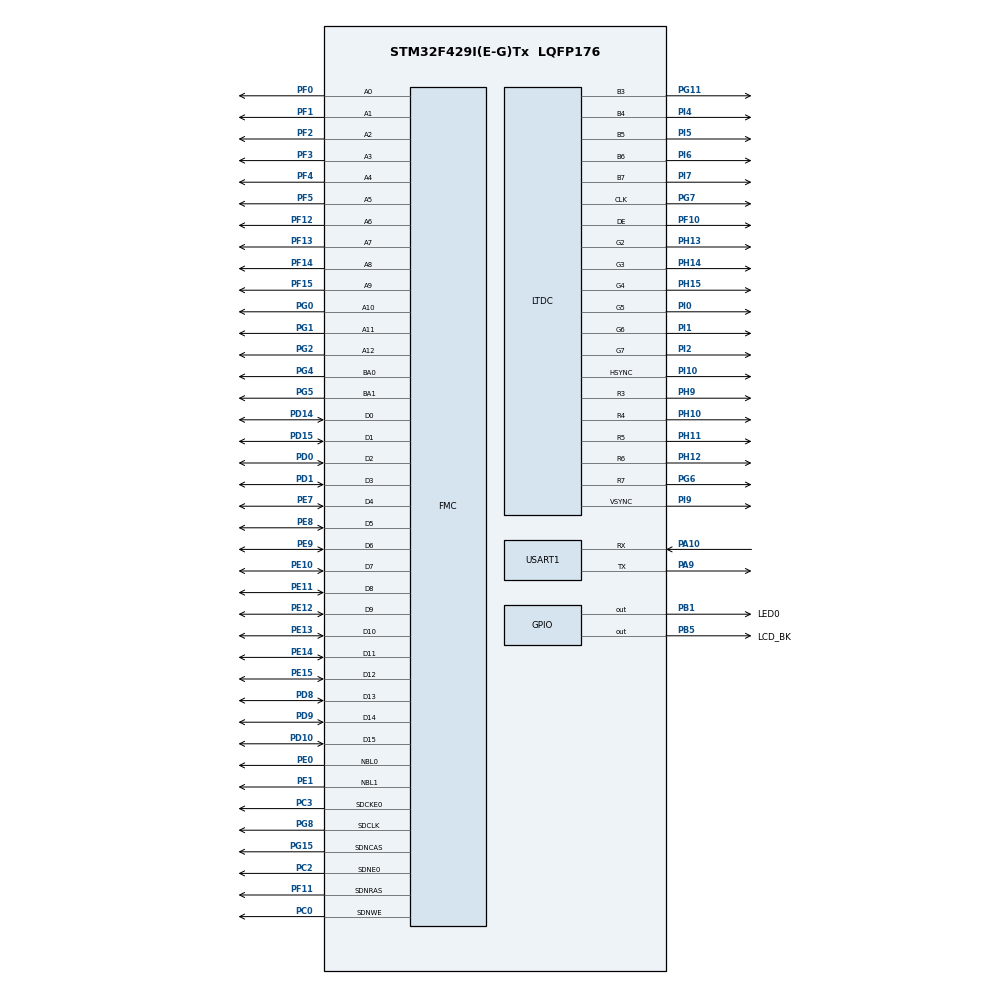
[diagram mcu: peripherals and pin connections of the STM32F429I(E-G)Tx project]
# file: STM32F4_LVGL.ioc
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DMA2D.ColorMode=DMA2D_OUTPUT_RGB565
FMC.CASLatency1=FMC_SDRAM_CAS_LATENCY_3
FMC.ColumnBitsNumber1=FMC_SDRAM_COLUMN_BITS_NUM_9
FMC.ExitSelfRefreshDelay1=7
FMC.LoadToActiveDelay1=2
FMC.RCDDelay1=2
FMC.RPDelay1=2
FMC.RPDelay2=2
FMC.ReadBurst1=FMC_SDRAM_RBURST_ENABLE
FMC.ReadBurst2=FMC_SDRAM_RBURST_ENABLE
FMC.ReadPipeDelay1=FMC_SDRAM_RPIPE_DELAY_0
FMC.RowCycleDelay1=7
FMC.RowCycleDelay2=7
FMC.SDClockPeriod1=FMC_SDRAM_CLOCK_PERIOD_2
FMC.SDClockPeriod2=FMC_SDRAM_CLOCK_PERIOD_2
FMC.SelfRefreshTime1=5
FMC.WriteRecoveryTime1=3
FREERTOS.Tasks01=defaultTask,0,128,StartDefaultTask,Default,NULL,Dynamic,NULL,NULL;myTask02,-3,128,StartTask02,Default,NULL,Dynamic,NULL,NULL;myTask03,-3,128,StartTask03,Default,NULL,Dynamic,NULL,NULL
LTDC.ActiveH=PIXELS_H
LTDC.ActiveW=PIXELS_W
LTDC.Alpha_L0=255
LTDC.FBStartAdress_L0=LTDC_BUFF_ADDR
LTDC.HBP=140
LTDC.HFP=160
LTDC.HSync=20
LTDC.Layers=0
LTDC.PixelFormat_L0=LTDC_PIXEL_FORMAT_RGB565
LTDC.VBP=20
LTDC.VFP=12
LTDC.VSync=3
LTDC.WindowX1_L0=PIXELS_W
LTDC.WindowY1_L0=PIXELS_H
Mcu.Family=STM32F4
Mcu.Name=STM32F429I(E-G)Tx
Mcu.Package=LQFP176
Mcu.UserConstants=LTDC_BUFF_ADDR,0xC0000000;PIXELS_W,1024;PIXELS_H,600;PIXELS_DIR,0
NVIC.PriorityGroup=NVIC_PRIORITYGROUP_4
NVIC.TIM1_UP_TIM10_IRQn=true\:15\:0\:false\:false\:true\:false\:false\:true\:true
NVIC.TimeBase=TIM1_UP_TIM10_IRQn
NVIC.TimeBaseIP=TIM1
NVIC.USART1_IRQn=true\:5\:0\:false\:false\:true\:true\:true\:true\:true
PA10.Mode=Asynchronous
PA10.Signal=USART1_RX
PA9.Mode=Asynchronous
PA9.Signal=USART1_TX
PB1.GPIO_Label=LED0
PB1.Signal=GPIO_Output
PB5.GPIO_Label=LCD_BK
PB5.Signal=GPIO_Output
PC0.Signal=FMC_SDNWE
PC14/OSC32_IN.Mode=LSE-External-Oscillator
PC14/OSC32_IN.Signal=RCC_OSC32_IN
PC15/OSC32_OUT.Mode=LSE-External-Oscillator
PC15/OSC32_OUT.Signal=RCC_OSC32_OUT
PC2.Mode=SdramChipSelect1_1
PC2.Signal=FMC_SDNE0
PC3.Mode=SdramChipSelect1_1
PC3.Signal=FMC_SDCKE0
PD0.Signal=FMC_D2_DA2
PD1.Signal=FMC_D3_DA3
PD10.Signal=FMC_D15_DA15
PD14.Signal=FMC_D0_DA0
PD15.Signal=FMC_D1_DA1
PD8.Signal=FMC_D13_DA13
PD9.Signal=FMC_D14_DA14
PE0.Signal=FMC_NBL0
PE1.Signal=FMC_NBL1
PE10.Signal=FMC_D7_DA7
PE11.Signal=FMC_D8_DA8
PE12.Signal=FMC_D9_DA9
PE13.Signal=FMC_D10_DA10
PE14.Signal=FMC_D11_DA11
PE15.Signal=FMC_D12_DA12
PE7.Signal=FMC_D4_DA4
PE8.Signal=FMC_D5_DA5
PE9.Signal=FMC_D6_DA6
PF0.Signal=FMC_A0
PF1.Signal=FMC_A1
PF10.Mode=RGB565
PF10.Signal=LTDC_DE
PF11.Signal=FMC_SDNRAS
PF12.Signal=FMC_A6
PF13.Signal=FMC_A7
PF14.Signal=FMC_A8
PF15.Signal=FMC_A9
PF2.Signal=FMC_A2
PF3.Signal=FMC_A3
PF4.Signal=FMC_A4
PF5.Signal=FMC_A5
PG0.Signal=FMC_A10
PG1.Signal=FMC_A11
PG11.Mode=RGB565
PG11.Signal=LTDC_B3
PG15.Signal=FMC_SDNCAS
PG2.Signal=FMC_A12
PG4.Signal=FMC_A14_BA0
PG5.Signal=FMC_A15_BA1
PG6.Mode=RGB565
PG6.Signal=LTDC_R7
PG7.Mode=RGB565
PG7.Signal=LTDC_CLK
PG8.Signal=FMC_SDCLK
PH0/OSC_IN.Mode=HSE-External-Oscillator
PH0/OSC_IN.Signal=RCC_OSC_IN
PH1/OSC_OUT.Mode=HSE-External-Oscillator
PH1/OSC_OUT.Signal=RCC_OSC_OUT
PH10.Mode=RGB565
PH10.Signal=LTDC_R4
PH11.Mode=RGB565
PH11.Signal=LTDC_R5
PH12.Mode=RGB565
PH12.Signal=LTDC_R6
PH13.Mode=RGB565
PH13.Signal=LTDC_G2
PH14.Mode=RGB565
PH14.Signal=LTDC_G3
PH15.Mode=RGB565
PH15.Signal=LTDC_G4
PH9.Mode=RGB565
PH9.Signal=LTDC_R3
PI0.Mode=RGB565
PI0.Signal=LTDC_G5
PI1.Mode=RGB565
PI1.Signal=LTDC_G6
PI10.Mode=RGB565
PI10.Signal=LTDC_HSYNC
PI2.Mode=RGB565
PI2.Signal=LTDC_G7
PI4.Mode=RGB565
PI4.Signal=LTDC_B4
PI5.Mode=RGB565
PI5.Signal=LTDC_B5
PI6.Mode=RGB565
PI6.Signal=LTDC_B6
PI7.Mode=RGB565
PI7.Signal=LTDC_B7
PI9.Mode=RGB565
PI9.Signal=LTDC_VSYNC
ProjectManager.HeapSize=0x200
ProjectManager.StackSize=0x400
ProjectManager.TargetToolchain=MDK-ARM V5.32
RCC.48MHZClocksFreq_Value=90000000
RCC.AHBFreq_Value=180000000
RCC.APB1CLKDivider=RCC_HCLK_DIV4
RCC.APB1Freq_Value=45000000
RCC.APB1TimFreq_Value=90000000
RCC.APB2CLKDivider=RCC_HCLK_DIV2
RCC.APB2Freq_Value=90000000
RCC.APB2TimFreq_Value=180000000
RCC.CortexFreq_Value=180000000
RCC.HCLKFreq_Value=180000000
RCC.HSE_VALUE=25000000
RCC.HSI_VALUE=16000000
RCC.PLLN=216
RCC.PLLSAIR=2
RCC.PLLSourceVirtual=RCC_PLLSOURCE_HSE
RCC.SYSCLKFreq_VALUE=180000000
RCC.SYSCLKSource=RCC_SYSCLKSOURCE_PLLCLK
RCC.VCOOutputFreq_Value=360000000
SH.FMC_A0.0=FMC_A0,13b-sda1
SH.FMC_A1.0=FMC_A1,13b-sda1
SH.FMC_A10.0=FMC_A10,13b-sda1
SH.FMC_A11.0=FMC_A11,13b-sda1
SH.FMC_A12.0=FMC_A12,13b-sda1
SH.FMC_A14_BA0.0=FMC_BA0,FourSdramBanks1
SH.FMC_A15_BA1.0=FMC_BA1,FourSdramBanks1
SH.FMC_A2.0=FMC_A2,13b-sda1
SH.FMC_A3.0=FMC_A3,13b-sda1
SH.FMC_A4.0=FMC_A4,13b-sda1
SH.FMC_A5.0=FMC_A5,13b-sda1
SH.FMC_A6.0=FMC_A6,13b-sda1
SH.FMC_A7.0=FMC_A7,13b-sda1
SH.FMC_A8.0=FMC_A8,13b-sda1
SH.FMC_A9.0=FMC_A9,13b-sda1
SH.FMC_D0_DA0.0=FMC_D0,sd-16b-d1
SH.FMC_D10_DA10.0=FMC_D10,sd-16b-d1
SH.FMC_D11_DA11.0=FMC_D11,sd-16b-d1
SH.FMC_D12_DA12.0=FMC_D12,sd-16b-d1
SH.FMC_D13_DA13.0=FMC_D13,sd-16b-d1
SH.FMC_D14_DA14.0=FMC_D14,sd-16b-d1
SH.FMC_D15_DA15.0=FMC_D15,sd-16b-d1
SH.FMC_D1_DA1.0=FMC_D1,sd-16b-d1
SH.FMC_D2_DA2.0=FMC_D2,sd-16b-d1
SH.FMC_D3_DA3.0=FMC_D3,sd-16b-d1
SH.FMC_D4_DA4.0=FMC_D4,sd-16b-d1
SH.FMC_D5_DA5.0=FMC_D5,sd-16b-d1
SH.FMC_D6_DA6.0=FMC_D6,sd-16b-d1
SH.FMC_D7_DA7.0=FMC_D7,sd-16b-d1
SH.FMC_D8_DA8.0=FMC_D8,sd-16b-d1
SH.FMC_D9_DA9.0=FMC_D9,sd-16b-d1
SH.FMC_NBL0.0=FMC_NBL0,Sd2ByteEnable1
SH.FMC_NBL1.0=FMC_NBL1,Sd2ByteEnable1
SH.FMC_SDCLK.0=FMC_SDCLK,13b-sda1
SH.FMC_SDNCAS.0=FMC_SDNCAS,13b-sda1
SH.FMC_SDNRAS.0=FMC_SDNRAS,13b-sda1
SH.FMC_SDNWE.0=FMC_SDNWE,13b-sda1
USART1.VirtualMode=VM_ASYNC
VP_DMA2D_VS_DMA2D.Mode=DMA2D_Activate
VP_FREERTOS_VS_CMSIS_V1.Mode=CMSIS_V1
VP_SYS_VS_tim1.Mode=TIM1
board=custom

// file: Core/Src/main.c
/* USER CODE BEGIN Header */
/**
  ******************************************************************************
  * @file           : main.c
  * @brief          : Main program body
  ******************************************************************************
  * @attention
  *
  * Copyright (c) 2024 STMicroelectronics.
  * All rights reserved.
  *
  * This software is licensed under terms that can be found in the LICENSE file
  * in the root directory of this software component.
  * If no LICENSE file comes with this software, it is provided AS-IS.
  *
  ******************************************************************************
  */
/* USER CODE END Header */
#include "main.h"
#include "cmsis_os.h"
#include "dma2d.h"
#include "ltdc.h"
#include "usart.h"
#include "gpio.h"
#include "fmc.h"

void SystemClock_Config(void);
void MX_FREERTOS_Init(void);

int main(void)
{

  /* MCU Configuration--------------------------------------------------------*/

  /* Reset of all peripherals, Initializes the Flash interface and the Systick. */
  HAL_Init();

  /* Configure the system clock */
  SystemClock_Config();

  /* Initialize all configured peripherals */
  MX_GPIO_Init();
  MX_USART1_UART_Init();
  MX_FMC_Init();
  MX_LTDC_Init();
  MX_DMA2D_Init();

  /* Call init function for freertos objects (in cmsis_os2.c) */
  MX_FREERTOS_Init();

  /* Start scheduler */
  osKernelStart();

  /* We should never get here as control is now taken by the scheduler */

  /* Infinite loop */
  /* USER CODE BEGIN WHILE */

  while (1)
  {
		HAL_Delay(500);

		//printf("hello\r\n");
    /* USER CODE END WHILE */

  }
}

void SystemClock_Config(void)
{
  RCC_OscInitTypeDef RCC_OscInitStruct = {0};
  RCC_ClkInitTypeDef RCC_ClkInitStruct = {0};

  /** Configure the main internal regulator output voltage
  */
  __HAL_RCC_PWR_CLK_ENABLE();
  __HAL_PWR_VOLTAGESCALING_CONFIG(PWR_REGULATOR_VOLTAGE_SCALE1);

  /** Initializes the RCC Oscillators according to the specified parameters
  * in the RCC_OscInitTypeDef structure.
  */
  RCC_OscInitStruct.OscillatorType = RCC_OSCILLATORTYPE_HSE;
  RCC_OscInitStruct.HSEState = RCC_HSE_ON;
  RCC_OscInitStruct.PLL.PLLState = RCC_PLL_ON;
  RCC_OscInitStruct.PLL.PLLSource = RCC_PLLSOURCE_HSE;
  RCC_OscInitStruct.PLL.PLLM = 16;
  RCC_OscInitStruct.PLL.PLLN = 216;
  RCC_OscInitStruct.PLL.PLLP = RCC_PLLP_DIV2;
  RCC_OscInitStruct.PLL.PLLQ = 4;
  if (HAL_RCC_OscConfig(&RCC_OscInitStruct) != HAL_OK)
  {
    Error_Handler();
  }

  /** Activate the Over-Drive mode
  */
  if (HAL_PWREx_EnableOverDrive() != HAL_OK)
  {
    Error_Handler();
  }

  /** Initializes the CPU, AHB and APB buses clocks
  */
  RCC_ClkInitStruct.ClockType = RCC_CLOCKTYPE_HCLK|RCC_CLOCKTYPE_SYSCLK
                              |RCC_CLOCKTYPE_PCLK1|RCC_CLOCKTYPE_PCLK2;
  RCC_ClkInitStruct.SYSCLKSource = RCC_SYSCLKSOURCE_PLLCLK;
  RCC_ClkInitStruct.AHBCLKDivider = RCC_SYSCLK_DIV1;
  RCC_ClkInitStruct.APB1CLKDivider = RCC_HCLK_DIV4;
  RCC_ClkInitStruct.APB2CLKDivider = RCC_HCLK_DIV2;

  if (HAL_RCC_ClockConfig(&RCC_ClkInitStruct, FLASH_LATENCY_5) != HAL_OK)
  {
    Error_Handler();
  }
}

void HAL_TIM_PeriodElapsedCallback(TIM_HandleTypeDef *htim)
{
  if (htim->Instance == TIM1) {
    HAL_IncTick();
  }
}

void Error_Handler(void)
{
  __disable_irq();
  while (1)
  {
  }
}

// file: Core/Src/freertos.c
/* USER CODE BEGIN Header */
/**
  ******************************************************************************
  * File Name          : freertos.c
  * Description        : Code for freertos applications
  ******************************************************************************
  * @attention
  *
  * Copyright (c) 2024 STMicroelectronics.
  * All rights reserved.
  *
  * This software is licensed under terms that can be found in the LICENSE file
  * in the root directory of this software component.
  * If no LICENSE file comes with this software, it is provided AS-IS.
  *
  ******************************************************************************
  */
/* USER CODE END Header */

#include "FreeRTOS.h"
#include "task.h"
#include "main.h"
#include "cmsis_os.h"

/* USER CODE BEGIN Includes */
#include "fmc.h"
#include "ltdc.h"
#include "stdio.h"
/* USER CODE END Includes */

osThreadId defaultTaskHandle;
osThreadId myTask02Handle;
osThreadId myTask03Handle;

void StartDefaultTask(void const * argument);
void StartTask02(void const * argument);
void StartTask03(void const * argument);

void MX_FREERTOS_Init(void); /* (MISRA C 2004 rule 8.1) */

/* GetIdleTaskMemory prototype (linked to static allocation support) */
void vApplicationGetIdleTaskMemory( StaticTask_t **ppxIdleTaskTCBBuffer, StackType_t **ppxIdleTaskStackBuffer, uint32_t *pulIdleTaskStackSize );

/* USER CODE BEGIN GET_IDLE_TASK_MEMORY */
static StaticTask_t xIdleTaskTCBBuffer;
static StackType_t xIdleStack[configMINIMAL_STACK_SIZE];

void vApplicationGetIdleTaskMemory( StaticTask_t **ppxIdleTaskTCBBuffer, StackType_t **ppxIdleTaskStackBuffer, uint32_t *pulIdleTaskStackSize )
{
  *ppxIdleTaskTCBBuffer = &xIdleTaskTCBBuffer;
  *ppxIdleTaskStackBuffer = &xIdleStack[0];
  *pulIdleTaskStackSize = configMINIMAL_STACK_SIZE;
  /* place for user code */
}
/* USER CODE END GET_IDLE_TASK_MEMORY */

void MX_FREERTOS_Init(void) {
  /* USER CODE BEGIN Init */
	SDRAM_Device_Init();

  /* USER CODE END Init */

  /* Create the thread(s) */
  /* definition and creation of defaultTask */
  osThreadDef(defaultTask, StartDefaultTask, osPriorityNormal, 0, 128);
  defaultTaskHandle = osThreadCreate(osThread(defaultTask), NULL);

  /* definition and creation of myTask02 */
  osThreadDef(myTask02, StartTask02, osPriorityIdle, 0, 128);
  myTask02Handle = osThreadCreate(osThread(myTask02), NULL);

  /* definition and creation of myTask03 */
  osThreadDef(myTask03, StartTask03, osPriorityIdle, 0, 128);
  myTask03Handle = osThreadCreate(osThread(myTask03), NULL);

}

void StartDefaultTask(void const * argument)
{
  for(;;)
  {
    osDelay(1);
  }
}

void StartTask02(void const * argument)
{
  /* USER CODE BEGIN StartTask02 */
  /* Infinite loop */
		osDelay(10);
	LTDC_Init();
	LTDC_Clear(YELLOW);
#if 0 //conflict with SDRAM_Test
	int retval;
	retval = SDRAM_Test();
	if(retval != SUCCESS)
		printf("SDRAM test error\r\n");
	else
		printf("SDRAM test OK!!!!\r\n");
#endif
  for(;;)
  {
		HAL_GPIO_TogglePin(LED0_GPIO_Port, LED0_Pin);

		LTDC_Clear(YELLOW);
		osDelay(500);
		LTDC_Clear(BLUE);
		osDelay(500);
		LTDC_Clear(RED);

		osDelay(500);
  }
  /* USER CODE END StartTask02 */
}

void StartTask03(void const * argument)
{
  /* USER CODE BEGIN StartTask03 */
  /* Infinite loop */
  for(;;)
  {
    osDelay(1000);
  }
  /* USER CODE END StartTask03 */
}
